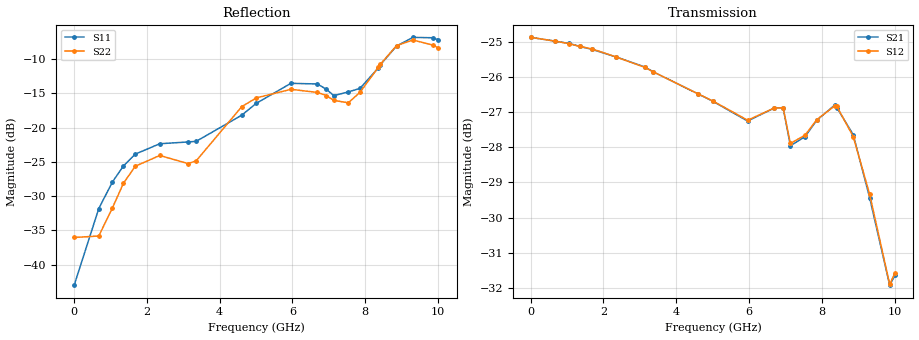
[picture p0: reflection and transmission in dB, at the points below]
! Device ID: PE43704
! Dir: z:\PE43704\PE43704_Char_1_20130516\PE43704\AMB\3p400V\24p00dB
! Serial: 14
! Insertion: A
! Impedance: 50 ohm
! Temp: Amb
! VDD: 3.400V
! Attenuation Step: 24.00dB
! IDD: 1.140341e-01mA
#  Hz  S  RI  R  50
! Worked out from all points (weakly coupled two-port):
!   401 points, 10 MHz to 10.01 GHz, reference 50 ohm
!   highest |S21| = -24.89 dB at 10 MHz (marker M1); lowest = -31.9 dB at 9.86 GHz (marker M2)
!   lowest |S11| = -43.0 dB at 10 MHz (marker M3), VSWR 1.01, Z = 50.7 + j0.0443 ohm
!   |S11| at or under -10 dB: start of sweep to 8.532 GHz
!   |S22| runs from -36.3 to -7.2 dB; largest |S21 - S12| = 0.00069
!   S11 on the Smith chart (normalised r, x): 10 MHz: 1.01, +0.00; 4.61 GHz: 0.80, +0.08; 8.41 GHz: 0.78, +0.47; 9.31 GHz: 0.51, +0.54; 10.01 GHz: 0.45, +0.33
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1e7  0.00709 0.000437  0.057 -0.000196  0.057 -0.000131  0.0158 0.000255
6.85e8  -0.0108 0.0233  0.0554 -0.01  0.0554 -0.01  -0.00177 0.0161
1.06e9  -0.0321 0.0241  0.0538 -0.0151  0.0538 -0.015  -0.0226 0.0128
1.36e9  -0.0491 0.0183  0.052 -0.0189  0.052 -0.0189  -0.0389 0.00443
1.685e9  -0.0635 0.00767  0.0498 -0.0229  0.0499 -0.0229  -0.0515 -0.00843
2.36e9  -0.0751 -0.0128  0.0443 -0.0299  0.0443 -0.0299  -0.0572 -0.0254
3.135e9  -0.077 -0.0151  0.0369 -0.0363  0.0368 -0.0363  -0.0531 -0.0126
3.36e9  -0.0788 -0.00907  0.0344 -0.0376  0.0344 -0.0376  -0.0571 -0.00348
4.61e9  -0.1115 0.052  0.0217 -0.0421  0.0219 -0.042  -0.1281 0.0612
5.01e9  -0.1309 0.0735  0.0187 -0.0423  0.0188 -0.0423  -0.1505 0.0661
5.96e9  -0.1811 0.1062  0.0104 -0.0421  0.0105 -0.0422  -0.1731 0.078
6.685e9  -0.1814 0.1011  0.0055 -0.0449  0.00549 -0.0449  -0.1575 0.0875
6.935e9  -0.1635 0.0968  0.000292 -0.0453  0.000346 -0.0453  -0.139 0.0998
7.135e9  -0.1482 0.0851  -0.000639 -0.04  -0.00056 -0.0403  -0.1148 0.1081
7.535e9  -0.1267 0.1301  -0.00056 -0.0412  -0.000708 -0.0414  -0.0757 0.1311
7.86e9  -0.0861 0.173  -0.00263 -0.0434  -0.00244 -0.0435  -0.0599 0.1709
8.36e9  -0.0502 0.2678  -0.0121 -0.0441  -0.012 -0.044  -0.0661 0.267
8.41e9  -0.0508 0.2809  -0.013 -0.0434  -0.013 -0.0436  -0.0709 0.2792
8.86e9  -0.0896 0.3823  -0.0199 -0.0364  -0.0199 -0.0361  -0.1198 0.3765
9.31e9  -0.1698 0.4208  -0.0193 -0.0277  -0.0197 -0.0279  -0.1937 0.3886
9.86e9  -0.2885 0.3466  -0.00956 -0.0235  -0.00975 -0.0235  -0.2943 0.2687
1.001e10  -0.3132 0.3031  -0.00645 -0.0254  -0.0065 -0.0256  -0.3119 0.216
